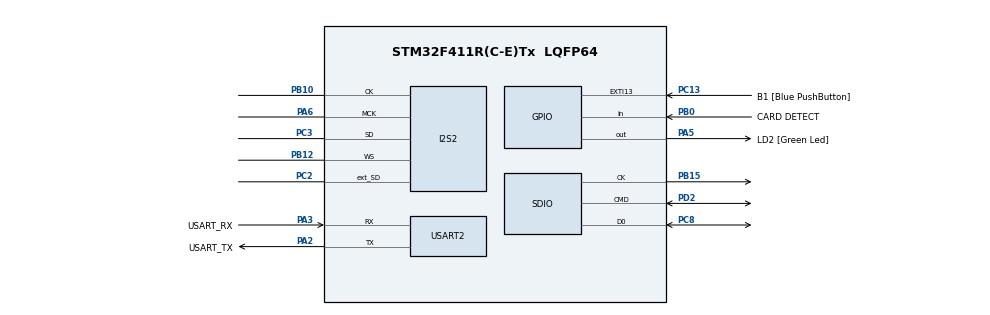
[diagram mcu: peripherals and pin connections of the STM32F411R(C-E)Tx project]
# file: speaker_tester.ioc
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Dma.I2S2_EXT_RX.1.Direction=DMA_PERIPH_TO_MEMORY
Dma.I2S2_EXT_RX.1.FIFOMode=DMA_FIFOMODE_DISABLE
Dma.I2S2_EXT_RX.1.Instance=DMA1_Stream3
Dma.I2S2_EXT_RX.1.MemDataAlignment=DMA_MDATAALIGN_HALFWORD
Dma.I2S2_EXT_RX.1.MemInc=DMA_MINC_ENABLE
Dma.I2S2_EXT_RX.1.Mode=DMA_CIRCULAR
Dma.I2S2_EXT_RX.1.PeriphDataAlignment=DMA_PDATAALIGN_HALFWORD
Dma.I2S2_EXT_RX.1.PeriphInc=DMA_PINC_DISABLE
Dma.I2S2_EXT_RX.1.Priority=DMA_PRIORITY_VERY_HIGH
Dma.Request0=SPI2_TX
Dma.Request1=I2S2_EXT_RX
Dma.Request2=SDIO_RX
Dma.Request3=SDIO_TX
Dma.SDIO_RX.2.Direction=DMA_PERIPH_TO_MEMORY
Dma.SDIO_RX.2.FIFOMode=DMA_FIFOMODE_ENABLE
Dma.SDIO_RX.2.FIFOThreshold=DMA_FIFO_THRESHOLD_FULL
Dma.SDIO_RX.2.Instance=DMA2_Stream3
Dma.SDIO_RX.2.MemBurst=DMA_MBURST_INC4
Dma.SDIO_RX.2.MemDataAlignment=DMA_MDATAALIGN_WORD
Dma.SDIO_RX.2.MemInc=DMA_MINC_ENABLE
Dma.SDIO_RX.2.Mode=DMA_PFCTRL
Dma.SDIO_RX.2.PeriphBurst=DMA_PBURST_INC4
Dma.SDIO_RX.2.PeriphDataAlignment=DMA_PDATAALIGN_WORD
Dma.SDIO_RX.2.PeriphInc=DMA_PINC_DISABLE
Dma.SDIO_RX.2.Priority=DMA_PRIORITY_HIGH
Dma.SDIO_TX.3.Direction=DMA_MEMORY_TO_PERIPH
Dma.SDIO_TX.3.FIFOMode=DMA_FIFOMODE_ENABLE
Dma.SDIO_TX.3.FIFOThreshold=DMA_FIFO_THRESHOLD_FULL
Dma.SDIO_TX.3.Instance=DMA2_Stream6
Dma.SDIO_TX.3.MemBurst=DMA_MBURST_INC4
Dma.SDIO_TX.3.MemDataAlignment=DMA_MDATAALIGN_WORD
Dma.SDIO_TX.3.MemInc=DMA_MINC_ENABLE
Dma.SDIO_TX.3.Mode=DMA_PFCTRL
Dma.SDIO_TX.3.PeriphBurst=DMA_PBURST_INC4
Dma.SDIO_TX.3.PeriphDataAlignment=DMA_PDATAALIGN_WORD
Dma.SDIO_TX.3.PeriphInc=DMA_PINC_DISABLE
Dma.SDIO_TX.3.Priority=DMA_PRIORITY_HIGH
Dma.SPI2_TX.0.Direction=DMA_MEMORY_TO_PERIPH
Dma.SPI2_TX.0.FIFOMode=DMA_FIFOMODE_DISABLE
Dma.SPI2_TX.0.Instance=DMA1_Stream4
Dma.SPI2_TX.0.MemDataAlignment=DMA_MDATAALIGN_HALFWORD
Dma.SPI2_TX.0.MemInc=DMA_MINC_ENABLE
Dma.SPI2_TX.0.Mode=DMA_CIRCULAR
Dma.SPI2_TX.0.PeriphDataAlignment=DMA_PDATAALIGN_HALFWORD
Dma.SPI2_TX.0.PeriphInc=DMA_PINC_DISABLE
Dma.SPI2_TX.0.Priority=DMA_PRIORITY_VERY_HIGH
FATFS.BSP.number=1
FATFS._USE_LFN=0
FATFS0.BSP.STBoard=false
FATFS0.BSP.api=Unknown
FATFS0.BSP.instance=PB0
FATFS0.BSP.ip=GPIO
FATFS0.BSP.mode=Input
FATFS0.BSP.name=Detect_SDIO
FATFS0.BSP.solution=PB0
I2S2.AudioFreq=I2S_AUDIOFREQ_48K
I2S2.DataFormat=I2S_DATAFORMAT_16B
I2S2.ErrorAudioFreq=0.02 %
I2S2.FullDuplexMode=I2S_FULLDUPLEXMODE_ENABLE
I2S2.Instance=SPI$Index
I2S2.RealAudioFreq=48.014 KHz
I2S2.VirtualMode=I2S_MODE_MASTER
Mcu.Family=STM32F4
Mcu.Name=STM32F411R(C-E)Tx
Mcu.Package=LQFP64
NVIC.DMA1_Stream3_IRQn=true\:0\:0\:false\:false\:true\:false\:true\:true
NVIC.DMA1_Stream4_IRQn=true\:0\:0\:false\:false\:true\:false\:true\:true
NVIC.DMA2_Stream3_IRQn=true\:0\:0\:false\:false\:true\:false\:true\:true
NVIC.DMA2_Stream6_IRQn=true\:0\:0\:false\:false\:true\:false\:true\:true
NVIC.EXTI15_10_IRQn=true\:0\:0\:false\:false\:true\:true\:true\:true
NVIC.PriorityGroup=NVIC_PRIORITYGROUP_4
PA13.GPIO_Label=TMS
PA13.Mode=Serial_Wire
PA13.Signal=SYS_JTMS-SWDIO
PA14.GPIO_Label=TCK
PA14.Mode=Serial_Wire
PA14.Signal=SYS_JTCK-SWCLK
PA2.GPIO_Label=USART_TX
PA2.Mode=Asynchronous
PA2.Signal=USART2_TX
PA3.GPIO_Label=USART_RX
PA3.Mode=Asynchronous
PA3.Signal=USART2_RX
PA5.GPIO_Label=LD2 [Green Led]
PA5.Signal=GPIO_Output
PA6.GPIO_Speed=GPIO_SPEED_FREQ_VERY_HIGH
PA6.Mode=Master_Clock_Activated
PA6.Signal=I2S2_MCK
PB0.GPIO_Label=CARD DETECT
PB0.GPIO_PuPd=GPIO_PULLUP
PB0.Signal=GPIO_Input
PB10.GPIO_Speed=GPIO_SPEED_FREQ_VERY_HIGH
PB10.Mode=Full_Duplex_Master
PB10.Signal=I2S2_CK
PB12.GPIO_Speed=GPIO_SPEED_FREQ_VERY_HIGH
PB12.Mode=Full_Duplex_Master
PB12.Signal=I2S2_WS
PB15.Mode=SD_1_bit
PB15.Signal=SDIO_CK
PB3.GPIO_Label=SWO
PB3.Signal=SYS_JTDO-SWO
PC13-ANTI_TAMP.GPIO_Label=B1 [Blue PushButton]
PC13-ANTI_TAMP.GPIO_ModeDefaultEXTI=GPIO_MODE_IT_FALLING
PC13-ANTI_TAMP.Signal=GPXTI13
PC14-OSC32_IN.Signal=RCC_OSC32_IN
PC15-OSC32_OUT.Signal=RCC_OSC32_OUT
PC2.GPIO_Speed=GPIO_SPEED_FREQ_VERY_HIGH
PC2.Mode=Full_Duplex_Master
PC2.Signal=I2S2_ext_SD
PC3.GPIO_Speed=GPIO_SPEED_FREQ_VERY_HIGH
PC3.Mode=Full_Duplex_Master
PC3.Signal=I2S2_SD
PC8.GPIO_PuPd=GPIO_PULLUP
PC8.Mode=SD_1_bit
PC8.Signal=SDIO_D0
PD2.GPIO_PuPd=GPIO_PULLUP
PD2.Mode=SD_1_bit
PD2.Signal=SDIO_CMD
PH0\ -\ OSC_IN.Signal=RCC_OSC_IN
PH1\ -\ OSC_OUT.Signal=RCC_OSC_OUT
ProjectManager.HeapSize=0x200
ProjectManager.StackSize=0x400
ProjectManager.TargetToolchain=STM32CubeIDE
RCC.48MHZClocksFreq_Value=48000000
RCC.AHBFreq_Value=96000000
RCC.APB1CLKDivider=RCC_HCLK_DIV2
RCC.APB1Freq_Value=48000000
RCC.APB1TimFreq_Value=96000000
RCC.APB2Freq_Value=96000000
RCC.APB2TimFreq_Value=96000000
RCC.CortexFreq_Value=96000000
RCC.FLatency-AdvancedSettings=FLASH_LATENCY_3
RCC.HCLKFreq_Value=96000000
RCC.HSE_VALUE=8000000
RCC.HSI_VALUE=16000000
RCC.PLLI2SN=295
RCC.PLLI2SR=3
RCC.SYSCLKFreq_VALUE=96000000
RCC.SYSCLKSource=RCC_SYSCLKSOURCE_PLLCLK
RCC.VCOOutputFreq_Value=192000000
SDIO.ClockBypass=SDIO_CLOCK_BYPASS_DISABLE
SDIO.ClockDiv=10
SDIO.HardwareFlowControl=SDIO_HARDWARE_FLOW_CONTROL_DISABLE
USART2.VirtualMode=VM_ASYNC
VP_FATFS_VS_SDIO.Mode=SDIO
board=NUCLEO-F411RE

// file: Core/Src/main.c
/* USER CODE BEGIN Header */
/**
  ******************************************************************************
  * @file           : main.c
  * @brief          : Main program body
  ******************************************************************************
  * @attention
  *
  * Copyright (c) 2026 STMicroelectronics.
  * All rights reserved.
  *
  * This software is licensed under terms that can be found in the LICENSE file
  * in the root directory of this software component.
  * If no LICENSE file comes with this software, it is provided AS-IS.
  *
  ******************************************************************************
  */
/* USER CODE END Header */
#include "main.h"
#include "fatfs.h"

/* USER CODE BEGIN Includes */
#include "stdio.h"
#include "sd_card.h"
#include <math.h>
#include <stdint.h>

/* USER CODE END Includes */

/* USER CODE BEGIN PD */
#define BUFFER_SIZE 4096

/* USER CODE END PD */

I2S_HandleTypeDef hi2s2;
DMA_HandleTypeDef hdma_spi2_tx;
DMA_HandleTypeDef hdma_i2s2_ext_rx;

SD_HandleTypeDef hsd;
DMA_HandleTypeDef hdma_sdio_rx;
DMA_HandleTypeDef hdma_sdio_tx;

UART_HandleTypeDef huart2;

/* USER CODE BEGIN PV */

const float TAU = 6.283185307f;
int16_t adcData[BUFFER_SIZE];
int16_t dacData[BUFFER_SIZE];
volatile uint8_t button_flag, start_stop_recording;
volatile uint8_t half_i2s, full_i2s;
volatile int debug_number;

// --- SWEEP-GENERAATTORIN MUUTTUJAT ---
float current_phase = 0.0f;
float current_freq = 20.0f;

//
const float SAMPLE_RATE = 48000.0f;
const float START_FREQ = 20.0f;
const float END_FREQ = 20000.0f;
const float DURATION = 5.0f;

/* USER CODE END PV */

void SystemClock_Config(void);
static void MX_GPIO_Init(void);
static void MX_DMA_Init(void);
static void MX_USART2_UART_Init(void);
static void MX_I2S2_Init(void);
static void MX_SDIO_SD_Init(void);

/* USER CODE BEGIN 0 */

// Function to calculate and fill the buffer with sine sweep data
void Fill_Sweep_Buffer(int16_t *buffer, int length) {
    // 1. Calculate frequency increment per sample (Hz per sample)
    float freq_step = (END_FREQ - START_FREQ) / (DURATION * SAMPLE_RATE);

    // 2. Loop through the buffer (i += 2 for Stereo: Left and Right)
    for (int i = 0; i < length; i += 2) {

        // --- A. Calculate Sine ---
        float sample = sinf(current_phase);

        // Scale to 16-bit (10000.0f is loud and clear for testing)
        int16_t value = (int16_t)(sample * 10000.0f);

        // --- B. Store in Buffer ---
        buffer[i]     = value; // Left Channel
        buffer[i + 1] = value; // Right Channel

        // --- C. Update Phase ---
        // Formula: 2*PI * Frequency / SampleRate
        float phase_increment = (TAU * current_freq) / SAMPLE_RATE;
        current_phase += phase_increment;

        // Keep phase within range 0 ... 2*PI
        if (current_phase > TAU) {
            current_phase -= TAU;
        }

        // --- D. Update Frequency (Sweep) ---
        current_freq += freq_step;

        // If sweep is finished (freq > max), reset to start frequency
        if (current_freq > END_FREQ) {
            current_freq = START_FREQ;
        }
    }
}

// --- CALLBACK FUNCTIONS ---

// 1. Half Transfer: DMA has played the first half -> refill
void HAL_I2SEx_TxRxHalfCpltCallback(I2S_HandleTypeDef *hi2s){
    Fill_Sweep_Buffer(&dacData[0], BUFFER_SIZE / 2);
    half_i2s = 1;
}

// 2. Transfer Complete: DMA has played the second half -> refill
void HAL_I2SEx_TxRxCpltCallback(I2S_HandleTypeDef *hi2s){
    Fill_Sweep_Buffer(&dacData[BUFFER_SIZE / 2], BUFFER_SIZE / 2);
    full_i2s = 1;
}

/* USER CODE END 0 */

int main(void)
{

  /* MCU Configuration--------------------------------------------------------*/

  /* Reset of all peripherals, Initializes the Flash interface and the Systick. */
  HAL_Init();

  /* Configure the system clock */
  SystemClock_Config();

  /* Initialize all configured peripherals */
  MX_GPIO_Init();
  MX_DMA_Init();
  MX_USART2_UART_Init();
  MX_I2S2_Init();
  MX_SDIO_SD_Init();
  MX_FATFS_Init();
  /* USER CODE BEGIN 2 */

//  Try to detect SD card, if not detected blink the led
  if (sd_card_init() != 0) {
  	  while(1){
	  		  HAL_GPIO_TogglePin(LD2_GPIO_Port, LD2_Pin);
	  		  HAL_Delay(100);
	  	  }

  }

  /* USER CODE END 2 */

  /* Infinite loop */
  /* USER CODE BEGIN WHILE */
  while (1)
  {

	  if(button_flag)
	  {
		  if(start_stop_recording)
		  {
			  start_stop_recording = 0;
		  	  stop_recording();
		  	  //a variable to check
		  	  debug_number = 1;
		  	  HAL_I2S_DMAStop(&hi2s2);
		  }

	  	  else
	  	  {
	  		  start_stop_recording = 1;
	  		  start_recording(I2S_AUDIOFREQ_48K);
	  		  debug_number = 2;
	  		  Fill_Sweep_Buffer(&dacData[0], BUFFER_SIZE);
	  		  //Hal_StatusTypeDef status = HAL_I2SEx_TransmitReceive_DMA(&hi2s2, (uint16_t *) dacData, (uint16_t *) adcData, BUFFER_SIZE);
	  		  if (HAL_I2SEx_TransmitReceive_DMA(&hi2s2, (uint16_t *)dacData, (uint16_t *)adcData, BUFFER_SIZE) != HAL_OK)
	  		    {

	  		        Error_Handler();
	  		    }

	  	  }

	  	  button_flag = 0;
	  }

	  if(start_stop_recording == 1 && half_i2s ==1)
	  {
		  HAL_GPIO_TogglePin(LD2_GPIO_Port, LD2_Pin);
		  write2wave_file((uint8_t *)&adcData[0], (BUFFER_SIZE/2) * 2);
		  half_i2s = 0;
	  }
	  if(start_stop_recording == 1 && full_i2s == 1)
	  {
		  write2wave_file((uint8_t *)&adcData[BUFFER_SIZE/2], (BUFFER_SIZE/2) * 2);
		  full_i2s = 0;
	  }

  }
    /* USER CODE END WHILE */

}

void SystemClock_Config(void)
{
  RCC_OscInitTypeDef RCC_OscInitStruct = {0};
  RCC_ClkInitTypeDef RCC_ClkInitStruct = {0};

  /** Configure the main internal regulator output voltage
  */
  __HAL_RCC_PWR_CLK_ENABLE();
  __HAL_PWR_VOLTAGESCALING_CONFIG(PWR_REGULATOR_VOLTAGE_SCALE1);

  /** Initializes the RCC Oscillators according to the specified parameters
  * in the RCC_OscInitTypeDef structure.
  */
  RCC_OscInitStruct.OscillatorType = RCC_OSCILLATORTYPE_HSI;
  RCC_OscInitStruct.HSIState = RCC_HSI_ON;
  RCC_OscInitStruct.HSICalibrationValue = RCC_HSICALIBRATION_DEFAULT;
  RCC_OscInitStruct.PLL.PLLState = RCC_PLL_ON;
  RCC_OscInitStruct.PLL.PLLSource = RCC_PLLSOURCE_HSI;
  RCC_OscInitStruct.PLL.PLLM = 8;
  RCC_OscInitStruct.PLL.PLLN = 72;
  RCC_OscInitStruct.PLL.PLLP = RCC_PLLP_DIV2;
  RCC_OscInitStruct.PLL.PLLQ = 3;
  if (HAL_RCC_OscConfig(&RCC_OscInitStruct) != HAL_OK)
  {
    Error_Handler();
  }

  /** Initializes the CPU, AHB and APB buses clocks
  */
  RCC_ClkInitStruct.ClockType = RCC_CLOCKTYPE_HCLK|RCC_CLOCKTYPE_SYSCLK
                              |RCC_CLOCKTYPE_PCLK1|RCC_CLOCKTYPE_PCLK2;
  RCC_ClkInitStruct.SYSCLKSource = RCC_SYSCLKSOURCE_PLLCLK;
  RCC_ClkInitStruct.AHBCLKDivider = RCC_SYSCLK_DIV1;
  RCC_ClkInitStruct.APB1CLKDivider = RCC_HCLK_DIV2;
  RCC_ClkInitStruct.APB2CLKDivider = RCC_HCLK_DIV1;

  if (HAL_RCC_ClockConfig(&RCC_ClkInitStruct, FLASH_LATENCY_2) != HAL_OK)
  {
    Error_Handler();
  }
}

static void MX_I2S2_Init(void)
{

  hi2s2.Instance = SPI2;
  hi2s2.Init.Mode = I2S_MODE_MASTER_TX;
  hi2s2.Init.Standard = I2S_STANDARD_PHILIPS;
  hi2s2.Init.DataFormat = I2S_DATAFORMAT_16B;
  hi2s2.Init.MCLKOutput = I2S_MCLKOUTPUT_ENABLE;
  hi2s2.Init.AudioFreq = I2S_AUDIOFREQ_48K;
  hi2s2.Init.CPOL = I2S_CPOL_LOW;
  hi2s2.Init.ClockSource = I2S_CLOCK_PLL;
  hi2s2.Init.FullDuplexMode = I2S_FULLDUPLEXMODE_ENABLE;
  if (HAL_I2S_Init(&hi2s2) != HAL_OK)
  {
    Error_Handler();
  }

}

static void MX_SDIO_SD_Init(void)
{

  hsd.Instance = SDIO;
  hsd.Init.ClockEdge = SDIO_CLOCK_EDGE_RISING;
  hsd.Init.ClockBypass = SDIO_CLOCK_BYPASS_DISABLE;
  hsd.Init.ClockPowerSave = SDIO_CLOCK_POWER_SAVE_DISABLE;
  hsd.Init.BusWide = SDIO_BUS_WIDE_1B;
  hsd.Init.HardwareFlowControl = SDIO_HARDWARE_FLOW_CONTROL_DISABLE;
  hsd.Init.ClockDiv = 4;

}

static void MX_USART2_UART_Init(void)
{

  huart2.Instance = USART2;
  huart2.Init.BaudRate = 115200;
  huart2.Init.WordLength = UART_WORDLENGTH_8B;
  huart2.Init.StopBits = UART_STOPBITS_1;
  huart2.Init.Parity = UART_PARITY_NONE;
  huart2.Init.Mode = UART_MODE_TX_RX;
  huart2.Init.HwFlowCtl = UART_HWCONTROL_NONE;
  huart2.Init.OverSampling = UART_OVERSAMPLING_16;
  if (HAL_UART_Init(&huart2) != HAL_OK)
  {
    Error_Handler();
  }

}

static void MX_DMA_Init(void)
{

  /* DMA controller clock enable */
  __HAL_RCC_DMA1_CLK_ENABLE();
  __HAL_RCC_DMA2_CLK_ENABLE();

  /* DMA interrupt init */
  /* DMA1_Stream3_IRQn interrupt configuration */
  HAL_NVIC_SetPriority(DMA1_Stream3_IRQn, 0, 0);
  HAL_NVIC_EnableIRQ(DMA1_Stream3_IRQn);
  /* DMA1_Stream4_IRQn interrupt configuration */
  HAL_NVIC_SetPriority(DMA1_Stream4_IRQn, 0, 0);
  HAL_NVIC_EnableIRQ(DMA1_Stream4_IRQn);
  /* DMA2_Stream3_IRQn interrupt configuration */
  HAL_NVIC_SetPriority(DMA2_Stream3_IRQn, 0, 0);
  HAL_NVIC_EnableIRQ(DMA2_Stream3_IRQn);
  /* DMA2_Stream6_IRQn interrupt configuration */
  HAL_NVIC_SetPriority(DMA2_Stream6_IRQn, 0, 0);
  HAL_NVIC_EnableIRQ(DMA2_Stream6_IRQn);

}

static void MX_GPIO_Init(void)
{
  GPIO_InitTypeDef GPIO_InitStruct = {0};

  /* GPIO Ports Clock Enable */
  __HAL_RCC_GPIOC_CLK_ENABLE();
  __HAL_RCC_GPIOH_CLK_ENABLE();
  __HAL_RCC_GPIOA_CLK_ENABLE();
  __HAL_RCC_GPIOB_CLK_ENABLE();
  __HAL_RCC_GPIOD_CLK_ENABLE();

  /*Configure GPIO pin Output Level */
  HAL_GPIO_WritePin(LD2_GPIO_Port, LD2_Pin, GPIO_PIN_RESET);

  /*Configure GPIO pin : B1_Pin */
  GPIO_InitStruct.Pin = B1_Pin;
  GPIO_InitStruct.Mode = GPIO_MODE_IT_FALLING;
  GPIO_InitStruct.Pull = GPIO_NOPULL;
  HAL_GPIO_Init(B1_GPIO_Port, &GPIO_InitStruct);

  /*Configure GPIO pin : LD2_Pin */
  GPIO_InitStruct.Pin = LD2_Pin;
  GPIO_InitStruct.Mode = GPIO_MODE_OUTPUT_PP;
  GPIO_InitStruct.Pull = GPIO_NOPULL;
  GPIO_InitStruct.Speed = GPIO_SPEED_FREQ_LOW;
  HAL_GPIO_Init(LD2_GPIO_Port, &GPIO_InitStruct);

  /*Configure GPIO pin : CARD_DETECT_Pin */
  GPIO_InitStruct.Pin = CARD_DETECT_Pin;
  GPIO_InitStruct.Mode = GPIO_MODE_INPUT;
  GPIO_InitStruct.Pull = GPIO_PULLUP;
  HAL_GPIO_Init(CARD_DETECT_GPIO_Port, &GPIO_InitStruct);

  /* EXTI interrupt init*/
  HAL_NVIC_SetPriority(EXTI15_10_IRQn, 0, 0);
  HAL_NVIC_EnableIRQ(EXTI15_10_IRQn);

}

/* USER CODE BEGIN 4 */

//void HAL_I2S_RxHalfCpltCallback(I2S_HandleTypeDef *hi2s)
//{
//	half_i2s = 1;
//}
//
//void HAL_I2S_RxCpltCallback(I2S_HandleTypeDef *hi2s)
//{
//	full_i2s = 1;
//}

void HAL_GPIO_EXTI_Callback(uint16_t GPIO_Pin)
{
	if(GPIO_Pin == B1_Pin){
		button_flag = 1;
	}
}

/* USER CODE END 4 */

void Error_Handler(void)
{
  __disable_irq();
  while (1)
  {
  }
}
